VERSION 5.7 ;
  NOWIREEXTENSIONATPIN ON ;
  DIVIDERCHAR "/" ;
  BUSBITCHARS "[]" ;
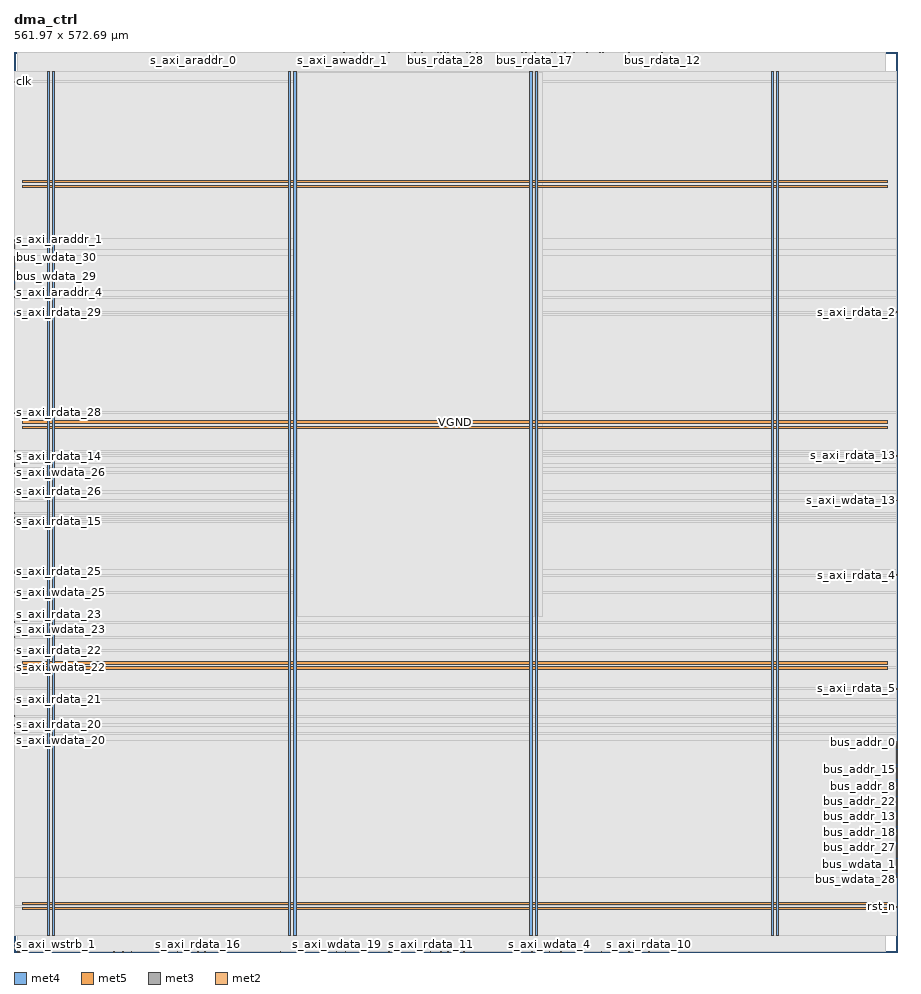
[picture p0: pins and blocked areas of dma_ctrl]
MACRO dma_ctrl
  CLASS BLOCK ;
  FOREIGN dma_ctrl ;
  ORIGIN 0.000 0.000 ;
  SIZE 561.970 BY 572.690 ;
  PIN VGND
    DIRECTION INOUT ;
    USE GROUND ;
    PORT
      LAYER met4 ;
        RECT 24.340 10.640 25.940 560.560 ;
    END
    PORT
      LAYER met4 ;
        RECT 177.940 10.640 179.540 560.560 ;
    END
    PORT
      LAYER met4 ;
        RECT 331.540 10.640 333.140 560.560 ;
    END
    PORT
      LAYER met4 ;
        RECT 485.140 10.640 486.740 560.560 ;
    END
    PORT
      LAYER met5 ;
        RECT 5.520 30.030 556.140 31.630 ;
    END
    PORT
      LAYER met5 ;
        RECT 5.520 183.210 556.140 184.810 ;
    END
    PORT
      LAYER met5 ;
        RECT 5.520 336.390 556.140 337.990 ;
    END
    PORT
      LAYER met5 ;
        RECT 5.520 489.570 556.140 491.170 ;
    END
  END VGND
  PIN VPWR
    DIRECTION INOUT ;
    USE POWER ;
    PORT
      LAYER met4 ;
        RECT 21.040 10.640 22.640 560.560 ;
    END
    PORT
      LAYER met4 ;
        RECT 174.640 10.640 176.240 560.560 ;
    END
    PORT
      LAYER met4 ;
        RECT 328.240 10.640 329.840 560.560 ;
    END
    PORT
      LAYER met4 ;
        RECT 481.840 10.640 483.440 560.560 ;
    END
    PORT
      LAYER met5 ;
        RECT 5.520 26.730 556.140 28.330 ;
    END
    PORT
      LAYER met5 ;
        RECT 5.520 179.910 556.140 181.510 ;
    END
    PORT
      LAYER met5 ;
        RECT 5.520 333.090 556.140 334.690 ;
    END
    PORT
      LAYER met5 ;
        RECT 5.520 486.270 556.140 487.870 ;
    END
  END VPWR
  PIN bus_addr_0
    DIRECTION OUTPUT ;
    USE SIGNAL ;
    ANTENNAGATEAREA 0.434700 ;
    ANTENNADIFFAREA 0.775300 ;
    PORT
      LAYER met3 ;
        RECT 561.370 133.320 561.970 133.920 ;
    END
  END bus_addr_0
  PIN bus_addr_1
    DIRECTION OUTPUT ;
    USE SIGNAL ;
    ANTENNAGATEAREA 0.434700 ;
    ANTENNADIFFAREA 0.775300 ;
    PORT
      LAYER met3 ;
        RECT 561.370 96.600 561.970 97.200 ;
    END
  END bus_addr_1
  PIN bus_addr_10
    DIRECTION OUTPUT ;
    USE SIGNAL ;
    ANTENNAGATEAREA 0.434700 ;
    ANTENNADIFFAREA 0.775300 ;
    PORT
      LAYER met3 ;
        RECT 561.370 123.800 561.970 124.400 ;
    END
  END bus_addr_10
  PIN bus_addr_11
    DIRECTION OUTPUT ;
    USE SIGNAL ;
    ANTENNAGATEAREA 0.434700 ;
    ANTENNADIFFAREA 0.775300 ;
    PORT
      LAYER met3 ;
        RECT 561.370 91.160 561.970 91.760 ;
    END
  END bus_addr_11
  PIN bus_addr_12
    DIRECTION OUTPUT ;
    USE SIGNAL ;
    ANTENNAGATEAREA 0.434700 ;
    ANTENNADIFFAREA 0.775300 ;
    PORT
      LAYER met3 ;
        RECT 561.370 129.240 561.970 129.840 ;
    END
  END bus_addr_12
  PIN bus_addr_13
    DIRECTION OUTPUT ;
    USE SIGNAL ;
    ANTENNAGATEAREA 0.434700 ;
    ANTENNADIFFAREA 0.775300 ;
    PORT
      LAYER met3 ;
        RECT 561.370 85.720 561.970 86.320 ;
    END
  END bus_addr_13
  PIN bus_addr_14
    DIRECTION OUTPUT ;
    USE SIGNAL ;
    ANTENNAGATEAREA 0.434700 ;
    ANTENNADIFFAREA 0.775300 ;
    PORT
      LAYER met3 ;
        RECT 561.370 84.360 561.970 84.960 ;
    END
  END bus_addr_14
  PIN bus_addr_15
    DIRECTION OUTPUT ;
    USE SIGNAL ;
    ANTENNAGATEAREA 0.434700 ;
    ANTENNADIFFAREA 0.775300 ;
    PORT
      LAYER met3 ;
        RECT 561.370 115.640 561.970 116.240 ;
    END
  END bus_addr_15
  PIN bus_addr_16
    DIRECTION OUTPUT ;
    USE SIGNAL ;
    ANTENNAGATEAREA 0.434700 ;
    ANTENNADIFFAREA 0.775300 ;
    PORT
      LAYER met3 ;
        RECT 561.370 83.000 561.970 83.600 ;
    END
  END bus_addr_16
  PIN bus_addr_17
    DIRECTION OUTPUT ;
    USE SIGNAL ;
    ANTENNAGATEAREA 0.434700 ;
    ANTENNADIFFAREA 0.775300 ;
    PORT
      LAYER met3 ;
        RECT 561.370 114.280 561.970 114.880 ;
    END
  END bus_addr_17
  PIN bus_addr_18
    DIRECTION OUTPUT ;
    USE SIGNAL ;
    ANTENNAGATEAREA 0.434700 ;
    ANTENNADIFFAREA 0.775300 ;
    PORT
      LAYER met3 ;
        RECT 561.370 80.280 561.970 80.880 ;
    END
  END bus_addr_18
  PIN bus_addr_19
    DIRECTION OUTPUT ;
    USE SIGNAL ;
    ANTENNAGATEAREA 0.434700 ;
    ANTENNADIFFAREA 0.775300 ;
    PORT
      LAYER met3 ;
        RECT 561.370 93.880 561.970 94.480 ;
    END
  END bus_addr_19
  PIN bus_addr_2
    DIRECTION OUTPUT ;
    USE SIGNAL ;
    ANTENNAGATEAREA 0.434700 ;
    ANTENNADIFFAREA 0.775300 ;
    PORT
      LAYER met3 ;
        RECT 561.370 78.920 561.970 79.520 ;
    END
  END bus_addr_2
  PIN bus_addr_20
    DIRECTION OUTPUT ;
    USE SIGNAL ;
    ANTENNAGATEAREA 0.434700 ;
    ANTENNADIFFAREA 0.775300 ;
    PORT
      LAYER met3 ;
        RECT 561.370 77.560 561.970 78.160 ;
    END
  END bus_addr_20
  PIN bus_addr_21
    DIRECTION OUTPUT ;
    USE SIGNAL ;
    ANTENNAGATEAREA 0.434700 ;
    ANTENNADIFFAREA 0.775300 ;
    PORT
      LAYER met3 ;
        RECT 561.370 125.160 561.970 125.760 ;
    END
  END bus_addr_21
  PIN bus_addr_22
    DIRECTION OUTPUT ;
    USE SIGNAL ;
    ANTENNAGATEAREA 0.434700 ;
    ANTENNADIFFAREA 0.775300 ;
    PORT
      LAYER met3 ;
        RECT 561.370 95.240 561.970 95.840 ;
    END
  END bus_addr_22
  PIN bus_addr_23
    DIRECTION OUTPUT ;
    USE SIGNAL ;
    ANTENNAGATEAREA 0.434700 ;
    ANTENNADIFFAREA 0.775300 ;
    PORT
      LAYER met3 ;
        RECT 561.370 74.840 561.970 75.440 ;
    END
  END bus_addr_23
  PIN bus_addr_24
    DIRECTION OUTPUT ;
    USE SIGNAL ;
    ANTENNAGATEAREA 0.434700 ;
    ANTENNADIFFAREA 0.775300 ;
    PORT
      LAYER met3 ;
        RECT 561.370 73.480 561.970 74.080 ;
    END
  END bus_addr_24
  PIN bus_addr_25
    DIRECTION OUTPUT ;
    USE SIGNAL ;
    ANTENNAGATEAREA 0.434700 ;
    ANTENNADIFFAREA 0.775300 ;
    PORT
      LAYER met3 ;
        RECT 561.370 72.120 561.970 72.720 ;
    END
  END bus_addr_25
  PIN bus_addr_26
    DIRECTION OUTPUT ;
    USE SIGNAL ;
    ANTENNAGATEAREA 0.434700 ;
    ANTENNADIFFAREA 0.775300 ;
    PORT
      LAYER met3 ;
        RECT 561.370 117.000 561.970 117.600 ;
    END
  END bus_addr_26
  PIN bus_addr_27
    DIRECTION OUTPUT ;
    USE SIGNAL ;
    ANTENNAGATEAREA 0.434700 ;
    ANTENNADIFFAREA 0.775300 ;
    PORT
      LAYER met3 ;
        RECT 561.370 70.760 561.970 71.360 ;
    END
  END bus_addr_27
  PIN bus_addr_28
    DIRECTION OUTPUT ;
    USE SIGNAL ;
    ANTENNAGATEAREA 0.434700 ;
    ANTENNADIFFAREA 0.775300 ;
    PORT
      LAYER met3 ;
        RECT 561.370 69.400 561.970 70.000 ;
    END
  END bus_addr_28
  PIN bus_addr_29
    DIRECTION OUTPUT ;
    USE SIGNAL ;
    ANTENNAGATEAREA 0.434700 ;
    ANTENNADIFFAREA 0.775300 ;
    PORT
      LAYER met3 ;
        RECT 561.370 68.040 561.970 68.640 ;
    END
  END bus_addr_29
  PIN bus_addr_3
    DIRECTION OUTPUT ;
    USE SIGNAL ;
    ANTENNAGATEAREA 0.434700 ;
    ANTENNADIFFAREA 0.775300 ;
    PORT
      LAYER met3 ;
        RECT 561.370 97.960 561.970 98.560 ;
    END
  END bus_addr_3
  PIN bus_addr_30
    DIRECTION OUTPUT ;
    USE SIGNAL ;
    ANTENNAGATEAREA 0.434700 ;
    ANTENNADIFFAREA 0.775300 ;
    PORT
      LAYER met3 ;
        RECT 561.370 66.680 561.970 67.280 ;
    END
  END bus_addr_30
  PIN bus_addr_31
    DIRECTION OUTPUT ;
    USE SIGNAL ;
    ANTENNAGATEAREA 0.434700 ;
    ANTENNADIFFAREA 0.775300 ;
    PORT
      LAYER met3 ;
        RECT 561.370 118.360 561.970 118.960 ;
    END
  END bus_addr_31
  PIN bus_addr_4
    DIRECTION OUTPUT ;
    USE SIGNAL ;
    ANTENNAGATEAREA 0.434700 ;
    ANTENNADIFFAREA 0.775300 ;
    PORT
      LAYER met3 ;
        RECT 561.370 63.960 561.970 64.560 ;
    END
  END bus_addr_4
  PIN bus_addr_5
    DIRECTION OUTPUT ;
    USE SIGNAL ;
    ANTENNAGATEAREA 0.434700 ;
    ANTENNADIFFAREA 0.775300 ;
    PORT
      LAYER met3 ;
        RECT 561.370 99.320 561.970 99.920 ;
    END
  END bus_addr_5
  PIN bus_addr_6
    DIRECTION OUTPUT ;
    USE SIGNAL ;
    ANTENNAGATEAREA 0.434700 ;
    ANTENNADIFFAREA 0.775300 ;
    PORT
      LAYER met3 ;
        RECT 561.370 62.600 561.970 63.200 ;
    END
  END bus_addr_6
  PIN bus_addr_7
    DIRECTION OUTPUT ;
    USE SIGNAL ;
    ANTENNAGATEAREA 0.434700 ;
    ANTENNADIFFAREA 0.775300 ;
    PORT
      LAYER met3 ;
        RECT 561.370 88.440 561.970 89.040 ;
    END
  END bus_addr_7
  PIN bus_addr_8
    DIRECTION OUTPUT ;
    USE SIGNAL ;
    ANTENNAGATEAREA 0.434700 ;
    ANTENNADIFFAREA 0.775300 ;
    PORT
      LAYER met3 ;
        RECT 561.370 104.760 561.970 105.360 ;
    END
  END bus_addr_8
  PIN bus_addr_9
    DIRECTION OUTPUT ;
    USE SIGNAL ;
    ANTENNAGATEAREA 0.434700 ;
    ANTENNADIFFAREA 0.775300 ;
    PORT
      LAYER met3 ;
        RECT 561.370 100.680 561.970 101.280 ;
    END
  END bus_addr_9
  PIN bus_rd
    DIRECTION OUTPUT ;
    USE SIGNAL ;
    ANTENNAGATEAREA 0.434700 ;
    ANTENNADIFFAREA 0.775300 ;
    PORT
      LAYER met3 ;
        RECT 0.000 423.000 0.600 423.600 ;
    END
  END bus_rd
  PIN bus_rdata_0
    DIRECTION INPUT ;
    USE SIGNAL ;
    ANTENNAGATEAREA 0.647700 ;
    ANTENNADIFFAREA 0.434700 ;
    PORT
      LAYER met2 ;
        RECT 310.130 572.410 310.410 572.690 ;
    END
  END bus_rdata_0
  PIN bus_rdata_1
    DIRECTION INPUT ;
    USE SIGNAL ;
    ANTENNAGATEAREA 0.647700 ;
    ANTENNADIFFAREA 0.434700 ;
    PORT
      LAYER met2 ;
        RECT 252.170 572.410 252.450 572.690 ;
    END
  END bus_rdata_1
  PIN bus_rdata_10
    DIRECTION INPUT ;
    USE SIGNAL ;
    ANTENNAGATEAREA 0.647700 ;
    ANTENNADIFFAREA 0.434700 ;
    PORT
      LAYER met2 ;
        RECT 342.330 572.410 342.610 572.690 ;
    END
  END bus_rdata_10
  PIN bus_rdata_11
    DIRECTION INPUT ;
    USE SIGNAL ;
    ANTENNAGATEAREA 0.647700 ;
    ANTENNADIFFAREA 0.434700 ;
    PORT
      LAYER met2 ;
        RECT 358.890 572.410 359.170 572.690 ;
    END
  END bus_rdata_11
  PIN bus_rdata_12
    DIRECTION INPUT ;
    USE SIGNAL ;
    ANTENNAGATEAREA 0.647700 ;
    ANTENNADIFFAREA 0.434700 ;
    PORT
      LAYER met2 ;
        RECT 412.250 572.410 412.530 572.690 ;
    END
  END bus_rdata_12
  PIN bus_rdata_13
    DIRECTION INPUT ;
    USE SIGNAL ;
    ANTENNAGATEAREA 0.647700 ;
    ANTENNADIFFAREA 0.434700 ;
    PORT
      LAYER met2 ;
        RECT 372.690 572.410 372.970 572.690 ;
    END
  END bus_rdata_13
  PIN bus_rdata_14
    DIRECTION INPUT ;
    USE SIGNAL ;
    ANTENNAGATEAREA 0.647700 ;
    ANTENNADIFFAREA 0.434700 ;
    PORT
      LAYER met2 ;
        RECT 392.010 572.410 392.290 572.690 ;
    END
  END bus_rdata_14
  PIN bus_rdata_15
    DIRECTION INPUT ;
    USE SIGNAL ;
    ANTENNAGATEAREA 0.647700 ;
    ANTENNADIFFAREA 0.434700 ;
    PORT
      LAYER met2 ;
        RECT 259.530 572.410 259.810 572.690 ;
    END
  END bus_rdata_15
  PIN bus_rdata_16
    DIRECTION INPUT ;
    USE SIGNAL ;
    ANTENNAGATEAREA 0.647700 ;
    ANTENNADIFFAREA 0.434700 ;
    PORT
      LAYER met2 ;
        RECT 364.410 572.410 364.690 572.690 ;
    END
  END bus_rdata_16
  PIN bus_rdata_17
    DIRECTION INPUT ;
    USE SIGNAL ;
    ANTENNAGATEAREA 0.647700 ;
    ANTENNADIFFAREA 0.434700 ;
    PORT
      LAYER met2 ;
        RECT 331.290 572.410 331.570 572.690 ;
    END
  END bus_rdata_17
  PIN bus_rdata_18
    DIRECTION INPUT ;
    USE SIGNAL ;
    ANTENNAGATEAREA 0.647700 ;
    ANTENNADIFFAREA 0.434700 ;
    PORT
      LAYER met2 ;
        RECT 325.770 572.410 326.050 572.690 ;
    END
  END bus_rdata_18
  PIN bus_rdata_19
    DIRECTION INPUT ;
    USE SIGNAL ;
    ANTENNAGATEAREA 0.647700 ;
    ANTENNADIFFAREA 0.434700 ;
    PORT
      LAYER met2 ;
        RECT 356.130 572.410 356.410 572.690 ;
    END
  END bus_rdata_19
  PIN bus_rdata_2
    DIRECTION INPUT ;
    USE SIGNAL ;
    ANTENNAGATEAREA 0.647700 ;
    ANTENNADIFFAREA 0.434700 ;
    PORT
      LAYER met2 ;
        RECT 303.690 572.410 303.970 572.690 ;
    END
  END bus_rdata_2
  PIN bus_rdata_20
    DIRECTION INPUT ;
    USE SIGNAL ;
    ANTENNAGATEAREA 0.647700 ;
    ANTENNADIFFAREA 0.434700 ;
    PORT
      LAYER met2 ;
        RECT 350.610 572.410 350.890 572.690 ;
    END
  END bus_rdata_20
  PIN bus_rdata_21
    DIRECTION INPUT ;
    USE SIGNAL ;
    ANTENNAGATEAREA 0.647700 ;
    ANTENNADIFFAREA 0.434700 ;
    PORT
      LAYER met2 ;
        RECT 391.090 572.410 391.370 572.690 ;
    END
  END bus_rdata_21
  PIN bus_rdata_22
    DIRECTION INPUT ;
    USE SIGNAL ;
    ANTENNAGATEAREA 0.647700 ;
    ANTENNADIFFAREA 0.434700 ;
    PORT
      LAYER met2 ;
        RECT 411.330 572.410 411.610 572.690 ;
    END
  END bus_rdata_22
  PIN bus_rdata_23
    DIRECTION INPUT ;
    USE SIGNAL ;
    ANTENNAGATEAREA 0.647700 ;
    ANTENNADIFFAREA 0.434700 ;
    PORT
      LAYER met2 ;
        RECT 288.970 572.410 289.250 572.690 ;
    END
  END bus_rdata_23
  PIN bus_rdata_24
    DIRECTION INPUT ;
    USE SIGNAL ;
    ANTENNAGATEAREA 0.647700 ;
    ANTENNADIFFAREA 0.434700 ;
    PORT
      LAYER met2 ;
        RECT 307.370 572.410 307.650 572.690 ;
    END
  END bus_rdata_24
  PIN bus_rdata_25
    DIRECTION INPUT ;
    USE SIGNAL ;
    ANTENNAGATEAREA 0.647700 ;
    ANTENNADIFFAREA 0.434700 ;
    PORT
      LAYER met2 ;
        RECT 324.850 572.410 325.130 572.690 ;
    END
  END bus_rdata_25
  PIN bus_rdata_26
    DIRECTION INPUT ;
    USE SIGNAL ;
    ANTENNAGATEAREA 0.647700 ;
    ANTENNADIFFAREA 0.434700 ;
    PORT
      LAYER met2 ;
        RECT 390.170 572.410 390.450 572.690 ;
    END
  END bus_rdata_26
  PIN bus_rdata_27
    DIRECTION INPUT ;
    USE SIGNAL ;
    ANTENNAGATEAREA 0.647700 ;
    ANTENNADIFFAREA 0.434700 ;
    PORT
      LAYER met2 ;
        RECT 409.490 572.410 409.770 572.690 ;
    END
  END bus_rdata_27
  PIN bus_rdata_28
    DIRECTION INPUT ;
    USE SIGNAL ;
    ANTENNAGATEAREA 0.647700 ;
    ANTENNADIFFAREA 0.434700 ;
    PORT
      LAYER met2 ;
        RECT 274.250 572.410 274.530 572.690 ;
    END
  END bus_rdata_28
  PIN bus_rdata_29
    DIRECTION INPUT ;
    USE SIGNAL ;
    ANTENNAGATEAREA 0.647700 ;
    ANTENNADIFFAREA 0.434700 ;
    PORT
      LAYER met2 ;
        RECT 373.610 572.410 373.890 572.690 ;
    END
  END bus_rdata_29
  PIN bus_rdata_3
    DIRECTION INPUT ;
    USE SIGNAL ;
    ANTENNAGATEAREA 0.647700 ;
    ANTENNADIFFAREA 0.434700 ;
    PORT
      LAYER met2 ;
        RECT 271.490 572.410 271.770 572.690 ;
    END
  END bus_rdata_3
  PIN bus_rdata_30
    DIRECTION INPUT ;
    USE SIGNAL ;
    ANTENNAGATEAREA 0.647700 ;
    ANTENNADIFFAREA 0.434700 ;
    PORT
      LAYER met2 ;
        RECT 344.170 572.410 344.450 572.690 ;
    END
  END bus_rdata_30
  PIN bus_rdata_31
    DIRECTION INPUT ;
    USE SIGNAL ;
    ANTENNAGATEAREA 0.647700 ;
    ANTENNADIFFAREA 0.434700 ;
    PORT
      LAYER met2 ;
        RECT 323.010 572.410 323.290 572.690 ;
    END
  END bus_rdata_31
  PIN bus_rdata_4
    DIRECTION INPUT ;
    USE SIGNAL ;
    ANTENNAGATEAREA 0.647700 ;
    ANTENNADIFFAREA 0.434700 ;
    PORT
      LAYER met2 ;
        RECT 266.890 572.410 267.170 572.690 ;
    END
  END bus_rdata_4
  PIN bus_rdata_5
    DIRECTION INPUT ;
    USE SIGNAL ;
    ANTENNAGATEAREA 0.647700 ;
    ANTENNADIFFAREA 0.434700 ;
    PORT
      LAYER met2 ;
        RECT 276.090 572.410 276.370 572.690 ;
    END
  END bus_rdata_5
  PIN bus_rdata_6
    DIRECTION INPUT ;
    USE SIGNAL ;
    ANTENNAGATEAREA 0.647700 ;
    ANTENNADIFFAREA 0.434700 ;
    PORT
      LAYER met2 ;
        RECT 295.410 572.410 295.690 572.690 ;
    END
  END bus_rdata_6
  PIN bus_rdata_7
    DIRECTION INPUT ;
    USE SIGNAL ;
    ANTENNAGATEAREA 0.647700 ;
    ANTENNADIFFAREA 0.434700 ;
    PORT
      LAYER met2 ;
        RECT 415.010 572.410 415.290 572.690 ;
    END
  END bus_rdata_7
  PIN bus_rdata_8
    DIRECTION INPUT ;
    USE SIGNAL ;
    ANTENNAGATEAREA 0.647700 ;
    ANTENNADIFFAREA 0.434700 ;
    PORT
      LAYER met2 ;
        RECT 408.570 572.410 408.850 572.690 ;
    END
  END bus_rdata_8
  PIN bus_rdata_9
    DIRECTION INPUT ;
    USE SIGNAL ;
    ANTENNAGATEAREA 0.647700 ;
    ANTENNADIFFAREA 0.434700 ;
    PORT
      LAYER met2 ;
        RECT 375.450 572.410 375.730 572.690 ;
    END
  END bus_rdata_9
  PIN bus_ready
    DIRECTION INPUT ;
    USE SIGNAL ;
    ANTENNAGATEAREA 0.647700 ;
    ANTENNADIFFAREA 0.434700 ;
    PORT
      LAYER met2 ;
        RECT 374.530 572.410 374.810 572.690 ;
    END
  END bus_ready
  PIN bus_wdata_0
    DIRECTION OUTPUT ;
    USE SIGNAL ;
    ANTENNAGATEAREA 0.434700 ;
    ANTENNADIFFAREA 0.775300 ;
    PORT
      LAYER met3 ;
        RECT 561.370 126.520 561.970 127.120 ;
    END
  END bus_wdata_0
  PIN bus_wdata_1
    DIRECTION OUTPUT ;
    USE SIGNAL ;
    ANTENNAGATEAREA 0.434700 ;
    ANTENNADIFFAREA 0.775300 ;
    PORT
      LAYER met3 ;
        RECT 561.370 59.880 561.970 60.480 ;
    END
  END bus_wdata_1
  PIN bus_wdata_10
    DIRECTION OUTPUT ;
    USE SIGNAL ;
    ANTENNAGATEAREA 0.434700 ;
    ANTENNADIFFAREA 0.775300 ;
    PORT
      LAYER met3 ;
        RECT 561.370 119.720 561.970 120.320 ;
    END
  END bus_wdata_10
  PIN bus_wdata_11
    DIRECTION OUTPUT ;
    USE SIGNAL ;
    ANTENNAGATEAREA 0.434700 ;
    ANTENNADIFFAREA 0.775300 ;
    PORT
      LAYER met3 ;
        RECT 561.370 102.040 561.970 102.640 ;
    END
  END bus_wdata_11
  PIN bus_wdata_12
    DIRECTION OUTPUT ;
    USE SIGNAL ;
    ANTENNAGATEAREA 0.434700 ;
    ANTENNADIFFAREA 0.775300 ;
    PORT
      LAYER met3 ;
        RECT 561.370 76.200 561.970 76.800 ;
    END
  END bus_wdata_12
  PIN bus_wdata_13
    DIRECTION OUTPUT ;
    USE SIGNAL ;
    ANTENNAGATEAREA 0.434700 ;
    ANTENNADIFFAREA 0.775300 ;
    PORT
      LAYER met3 ;
        RECT 561.370 131.960 561.970 132.560 ;
    END
  END bus_wdata_13
  PIN bus_wdata_14
    DIRECTION OUTPUT ;
    USE SIGNAL ;
    ANTENNAGATEAREA 0.434700 ;
    ANTENNADIFFAREA 0.775300 ;
    PORT
      LAYER met3 ;
        RECT 561.370 57.160 561.970 57.760 ;
    END
  END bus_wdata_14
  PIN bus_wdata_15
    DIRECTION OUTPUT ;
    USE SIGNAL ;
    ANTENNAGATEAREA 0.434700 ;
    ANTENNADIFFAREA 0.775300 ;
    PORT
      LAYER met3 ;
        RECT 561.370 103.400 561.970 104.000 ;
    END
  END bus_wdata_15
  PIN bus_wdata_16
    DIRECTION OUTPUT ;
    USE SIGNAL ;
    ANTENNAGATEAREA 0.434700 ;
    ANTENNADIFFAREA 0.775300 ;
    PORT
      LAYER met3 ;
        RECT 561.370 81.640 561.970 82.240 ;
    END
  END bus_wdata_16
  PIN bus_wdata_17
    DIRECTION OUTPUT ;
    USE SIGNAL ;
    ANTENNAGATEAREA 0.434700 ;
    ANTENNADIFFAREA 0.775300 ;
    PORT
      LAYER met3 ;
        RECT 561.370 55.800 561.970 56.400 ;
    END
  END bus_wdata_17
  PIN bus_wdata_18
    DIRECTION OUTPUT ;
    USE SIGNAL ;
    ANTENNAGATEAREA 0.434700 ;
    ANTENNADIFFAREA 0.775300 ;
    PORT
      LAYER met3 ;
        RECT 561.370 127.880 561.970 128.480 ;
    END
  END bus_wdata_18
  PIN bus_wdata_19
    DIRECTION OUTPUT ;
    USE SIGNAL ;
    ANTENNAGATEAREA 0.434700 ;
    ANTENNADIFFAREA 0.775300 ;
    PORT
      LAYER met3 ;
        RECT 561.370 121.080 561.970 121.680 ;
    END
  END bus_wdata_19
  PIN bus_wdata_2
    DIRECTION OUTPUT ;
    USE SIGNAL ;
    ANTENNAGATEAREA 0.434700 ;
    ANTENNADIFFAREA 0.775300 ;
    PORT
      LAYER met3 ;
        RECT 561.370 130.600 561.970 131.200 ;
    END
  END bus_wdata_2
  PIN bus_wdata_20
    DIRECTION OUTPUT ;
    USE SIGNAL ;
    ANTENNAGATEAREA 0.434700 ;
    ANTENNADIFFAREA 0.775300 ;
    PORT
      LAYER met3 ;
        RECT 561.370 108.840 561.970 109.440 ;
    END
  END bus_wdata_20
  PIN bus_wdata_21
    DIRECTION OUTPUT ;
    USE SIGNAL ;
    ANTENNAGATEAREA 0.434700 ;
    ANTENNADIFFAREA 0.775300 ;
    PORT
      LAYER met3 ;
        RECT 561.370 92.520 561.970 93.120 ;
    END
  END bus_wdata_21
  PIN bus_wdata_22
    DIRECTION OUTPUT ;
    USE SIGNAL ;
    ANTENNAGATEAREA 0.434700 ;
    ANTENNADIFFAREA 0.775300 ;
    PORT
      LAYER met3 ;
        RECT 561.370 106.120 561.970 106.720 ;
    END
  END bus_wdata_22
  PIN bus_wdata_23
    DIRECTION OUTPUT ;
    USE SIGNAL ;
    ANTENNAGATEAREA 0.434700 ;
    ANTENNADIFFAREA 0.775300 ;
    PORT
      LAYER met3 ;
        RECT 561.370 61.240 561.970 61.840 ;
    END
  END bus_wdata_23
  PIN bus_wdata_24
    DIRECTION OUTPUT ;
    USE SIGNAL ;
    ANTENNAGATEAREA 0.434700 ;
    ANTENNADIFFAREA 0.775300 ;
    PORT
      LAYER met3 ;
        RECT 561.370 58.520 561.970 59.120 ;
    END
  END bus_wdata_24
  PIN bus_wdata_25
    DIRECTION OUTPUT ;
    USE SIGNAL ;
    ANTENNAGATEAREA 0.434700 ;
    ANTENNADIFFAREA 0.775300 ;
    PORT
      LAYER met3 ;
        RECT 561.370 51.720 561.970 52.320 ;
    END
  END bus_wdata_25
  PIN bus_wdata_26
    DIRECTION OUTPUT ;
    USE SIGNAL ;
    ANTENNAGATEAREA 0.434700 ;
    ANTENNADIFFAREA 0.775300 ;
    PORT
      LAYER met3 ;
        RECT 561.370 107.480 561.970 108.080 ;
    END
  END bus_wdata_26
  PIN bus_wdata_27
    DIRECTION OUTPUT ;
    USE SIGNAL ;
    ANTENNAGATEAREA 0.434700 ;
    ANTENNADIFFAREA 0.775300 ;
    PORT
      LAYER met3 ;
        RECT 561.370 54.440 561.970 55.040 ;
    END
  END bus_wdata_27
  PIN bus_wdata_28
    DIRECTION OUTPUT ;
    USE SIGNAL ;
    ANTENNAGATEAREA 0.434700 ;
    ANTENNADIFFAREA 0.775300 ;
    PORT
      LAYER met3 ;
        RECT 561.370 50.360 561.970 50.960 ;
    END
  END bus_wdata_28
  PIN bus_wdata_29
    DIRECTION OUTPUT ;
    USE SIGNAL ;
    ANTENNAGATEAREA 0.434700 ;
    ANTENNADIFFAREA 0.775300 ;
    PORT
      LAYER met3 ;
        RECT 0.000 429.800 0.600 430.400 ;
    END
  END bus_wdata_29
  PIN bus_wdata_3
    DIRECTION OUTPUT ;
    USE SIGNAL ;
    ANTENNAGATEAREA 0.434700 ;
    ANTENNADIFFAREA 0.775300 ;
    PORT
      LAYER met3 ;
        RECT 561.370 112.920 561.970 113.520 ;
    END
  END bus_wdata_3
  PIN bus_wdata_30
    DIRECTION OUTPUT ;
    USE SIGNAL ;
    ANTENNAGATEAREA 0.434700 ;
    ANTENNADIFFAREA 0.775300 ;
    PORT
      LAYER met3 ;
        RECT 0.000 436.600 0.600 437.200 ;
    END
  END bus_wdata_30
  PIN bus_wdata_31
    DIRECTION OUTPUT ;
    USE SIGNAL ;
    ANTENNAGATEAREA 0.434700 ;
    ANTENNADIFFAREA 0.775300 ;
    PORT
      LAYER met3 ;
        RECT 0.000 432.520 0.600 433.120 ;
    END
  END bus_wdata_31
  PIN bus_wdata_4
    DIRECTION OUTPUT ;
    USE SIGNAL ;
    ANTENNAGATEAREA 0.434700 ;
    ANTENNADIFFAREA 0.775300 ;
    PORT
      LAYER met3 ;
        RECT 561.370 122.440 561.970 123.040 ;
    END
  END bus_wdata_4
  PIN bus_wdata_5
    DIRECTION OUTPUT ;
    USE SIGNAL ;
    ANTENNAGATEAREA 0.434700 ;
    ANTENNADIFFAREA 0.775300 ;
    PORT
      LAYER met3 ;
        RECT 561.370 53.080 561.970 53.680 ;
    END
  END bus_wdata_5
  PIN bus_wdata_6
    DIRECTION OUTPUT ;
    USE SIGNAL ;
    ANTENNAGATEAREA 0.434700 ;
    ANTENNADIFFAREA 0.775300 ;
    PORT
      LAYER met3 ;
        RECT 561.370 89.800 561.970 90.400 ;
    END
  END bus_wdata_6
  PIN bus_wdata_7
    DIRECTION OUTPUT ;
    USE SIGNAL ;
    ANTENNAGATEAREA 0.434700 ;
    ANTENNADIFFAREA 0.775300 ;
    PORT
      LAYER met3 ;
        RECT 561.370 49.000 561.970 49.600 ;
    END
  END bus_wdata_7
  PIN bus_wdata_8
    DIRECTION OUTPUT ;
    USE SIGNAL ;
    ANTENNAGATEAREA 0.434700 ;
    ANTENNADIFFAREA 0.775300 ;
    PORT
      LAYER met3 ;
        RECT 561.370 110.200 561.970 110.800 ;
    END
  END bus_wdata_8
  PIN bus_wdata_9
    DIRECTION OUTPUT ;
    USE SIGNAL ;
    ANTENNAGATEAREA 0.434700 ;
    ANTENNADIFFAREA 0.775300 ;
    PORT
      LAYER met3 ;
        RECT 561.370 47.640 561.970 48.240 ;
    END
  END bus_wdata_9
  PIN bus_wr
    DIRECTION OUTPUT ;
    USE SIGNAL ;
    ANTENNAGATEAREA 0.434700 ;
    ANTENNADIFFAREA 0.775300 ;
    PORT
      LAYER met3 ;
        RECT 0.000 431.160 0.600 431.760 ;
    END
  END bus_wr
  PIN clk
    DIRECTION INPUT ;
    USE SIGNAL ;
    ANTENNAGATEAREA 1.286700 ;
    ANTENNADIFFAREA 0.434700 ;
    PORT
      LAYER met3 ;
        RECT 0.000 553.560 0.600 554.160 ;
    END
  END clk
  PIN irq
    DIRECTION OUTPUT ;
    USE SIGNAL ;
    ANTENNAGATEAREA 0.434700 ;
    ANTENNADIFFAREA 0.775300 ;
    PORT
      LAYER met3 ;
        RECT 0.000 433.880 0.600 434.480 ;
    END
  END irq
  PIN rst_n
    DIRECTION INPUT ;
    USE SIGNAL ;
    ANTENNAGATEAREA 0.631200 ;
    ANTENNADIFFAREA 0.434700 ;
    PORT
      LAYER met3 ;
        RECT 561.370 28.600 561.970 29.200 ;
    END
  END rst_n
  PIN s_axi_araddr_0
    DIRECTION INPUT ;
    USE SIGNAL ;
    ANTENNAGATEAREA 0.647700 ;
    ANTENNADIFFAREA 0.434700 ;
    PORT
      LAYER met2 ;
        RECT 114.170 572.410 114.450 572.690 ;
    END
  END s_axi_araddr_0
  PIN s_axi_araddr_1
    DIRECTION INPUT ;
    USE SIGNAL ;
    ANTENNAGATEAREA 0.647700 ;
    ANTENNADIFFAREA 0.434700 ;
    PORT
      LAYER met3 ;
        RECT 0.000 452.920 0.600 453.520 ;
    END
  END s_axi_araddr_1
  PIN s_axi_araddr_10
    DIRECTION INPUT ;
    USE SIGNAL ;
    ANTENNAGATEAREA 0.647700 ;
    ANTENNADIFFAREA 0.434700 ;
    PORT
      LAYER met3 ;
        RECT 0.000 451.560 0.600 452.160 ;
    END
  END s_axi_araddr_10
  PIN s_axi_araddr_11
    DIRECTION INPUT ;
    USE SIGNAL ;
    ANTENNAGATEAREA 0.647700 ;
    ANTENNADIFFAREA 0.434700 ;
    PORT
      LAYER met2 ;
        RECT 136.250 572.410 136.530 572.690 ;
    END
  END s_axi_araddr_11
  PIN s_axi_araddr_2
    DIRECTION INPUT ;
    USE SIGNAL ;
    ANTENNAGATEAREA 0.647700 ;
    ANTENNADIFFAREA 0.434700 ;
    PORT
      LAYER met3 ;
        RECT 0.000 437.960 0.600 438.560 ;
    END
  END s_axi_araddr_2
  PIN s_axi_araddr_3
    DIRECTION INPUT ;
    USE SIGNAL ;
    ANTENNAGATEAREA 0.647700 ;
    ANTENNADIFFAREA 0.434700 ;
    PORT
      LAYER met3 ;
        RECT 0.000 440.680 0.600 441.280 ;
    END
  END s_axi_araddr_3
  PIN s_axi_araddr_4
    DIRECTION INPUT ;
    USE SIGNAL ;
    ANTENNAGATEAREA 0.647700 ;
    ANTENNADIFFAREA 0.434700 ;
    PORT
      LAYER met3 ;
        RECT 0.000 424.360 0.600 424.960 ;
    END
  END s_axi_araddr_4
  PIN s_axi_araddr_5
    DIRECTION INPUT ;
    USE SIGNAL ;
    ANTENNAGATEAREA 0.647700 ;
    ANTENNADIFFAREA 0.434700 ;
    PORT
      LAYER met3 ;
        RECT 0.000 447.480 0.600 448.080 ;
    END
  END s_axi_araddr_5
  PIN s_axi_araddr_6
    DIRECTION INPUT ;
    USE SIGNAL ;
    ANTENNAGATEAREA 0.647700 ;
    ANTENNADIFFAREA 0.434700 ;
    PORT
      LAYER met3 ;
        RECT 0.000 427.080 0.600 427.680 ;
    END
  END s_axi_araddr_6
  PIN s_axi_araddr_7
    DIRECTION INPUT ;
    USE SIGNAL ;
    ANTENNAGATEAREA 0.647700 ;
    ANTENNADIFFAREA 0.434700 ;
    PORT
      LAYER met2 ;
        RECT 152.810 572.410 153.090 572.690 ;
    END
  END s_axi_araddr_7
  PIN s_axi_araddr_8
    DIRECTION INPUT ;
    USE SIGNAL ;
    ANTENNAGATEAREA 0.647700 ;
    ANTENNADIFFAREA 0.434700 ;
    PORT
      LAYER met3 ;
        RECT 0.000 428.440 0.600 429.040 ;
    END
  END s_axi_araddr_8
  PIN s_axi_araddr_9
    DIRECTION INPUT ;
    USE SIGNAL ;
    ANTENNAGATEAREA 0.647700 ;
    ANTENNADIFFAREA 0.434700 ;
    PORT
      LAYER met2 ;
        RECT 99.450 572.410 99.730 572.690 ;
    END
  END s_axi_araddr_9
  PIN s_axi_arready
    DIRECTION OUTPUT ;
    USE SIGNAL ;
    ANTENNAGATEAREA 0.434700 ;
    ANTENNADIFFAREA 1.137600 ;
    PORT
      LAYER met2 ;
        RECT 169.370 572.410 169.650 572.690 ;
    END
  END s_axi_arready
  PIN s_axi_arvalid
    DIRECTION INPUT ;
    USE SIGNAL ;
    ANTENNAGATEAREA 0.647700 ;
    ANTENNADIFFAREA 0.434700 ;
    PORT
      LAYER met2 ;
        RECT 167.530 572.410 167.810 572.690 ;
    END
  END s_axi_arvalid
  PIN s_axi_awaddr_0
    DIRECTION INPUT ;
    USE SIGNAL ;
    ANTENNAGATEAREA 0.647700 ;
    ANTENNADIFFAREA 0.434700 ;
    PORT
      LAYER met2 ;
        RECT 222.730 572.410 223.010 572.690 ;
    END
  END s_axi_awaddr_0
  PIN s_axi_awaddr_1
    DIRECTION INPUT ;
    USE SIGNAL ;
    ANTENNAGATEAREA 0.647700 ;
    ANTENNADIFFAREA 0.434700 ;
    PORT
      LAYER met2 ;
        RECT 208.930 572.410 209.210 572.690 ;
    END
  END s_axi_awaddr_1
  PIN s_axi_awaddr_10
    DIRECTION INPUT ;
    USE SIGNAL ;
    ANTENNAGATEAREA 0.647700 ;
    ANTENNADIFFAREA 0.434700 ;
    PORT
      LAYER met2 ;
        RECT 221.810 572.410 222.090 572.690 ;
    END
  END s_axi_awaddr_10
  PIN s_axi_awaddr_11
    DIRECTION INPUT ;
    USE SIGNAL ;
    ANTENNAGATEAREA 0.647700 ;
    ANTENNADIFFAREA 0.434700 ;
    PORT
      LAYER met2 ;
        RECT 209.850 572.410 210.130 572.690 ;
    END
  END s_axi_awaddr_11
  PIN s_axi_awaddr_2
    DIRECTION INPUT ;
    USE SIGNAL ;
    ANTENNAGATEAREA 0.647700 ;
    ANTENNADIFFAREA 0.434700 ;
    PORT
      LAYER met2 ;
        RECT 273.330 572.410 273.610 572.690 ;
    END
  END s_axi_awaddr_2
  PIN s_axi_awaddr_3
    DIRECTION INPUT ;
    USE SIGNAL ;
    ANTENNAGATEAREA 0.647700 ;
    ANTENNADIFFAREA 0.434700 ;
    PORT
      LAYER met2 ;
        RECT 256.770 572.410 257.050 572.690 ;
    END
  END s_axi_awaddr_3
  PIN s_axi_awaddr_4
    DIRECTION INPUT ;
    USE SIGNAL ;
    ANTENNAGATEAREA 0.647700 ;
    ANTENNADIFFAREA 0.434700 ;
    PORT
      LAYER met2 ;
        RECT 272.410 572.410 272.690 572.690 ;
    END
  END s_axi_awaddr_4
  PIN s_axi_awaddr_5
    DIRECTION INPUT ;
    USE SIGNAL ;
    ANTENNAGATEAREA 0.647700 ;
    ANTENNADIFFAREA 0.434700 ;
    PORT
      LAYER met2 ;
        RECT 210.770 572.410 211.050 572.690 ;
    END
  END s_axi_awaddr_5
  PIN s_axi_awaddr_6
    DIRECTION INPUT ;
    USE SIGNAL ;
    ANTENNAGATEAREA 0.647700 ;
    ANTENNADIFFAREA 0.434700 ;
    PORT
      LAYER met2 ;
        RECT 223.650 572.410 223.930 572.690 ;
    END
  END s_axi_awaddr_6
  PIN s_axi_awaddr_7
    DIRECTION INPUT ;
    USE SIGNAL ;
    ANTENNAGATEAREA 0.647700 ;
    ANTENNADIFFAREA 0.434700 ;
    PORT
      LAYER met2 ;
        RECT 238.370 572.410 238.650 572.690 ;
    END
  END s_axi_awaddr_7
  PIN s_axi_awaddr_8
    DIRECTION INPUT ;
    USE SIGNAL ;
    ANTENNAGATEAREA 0.647700 ;
    ANTENNADIFFAREA 0.434700 ;
    PORT
      LAYER met2 ;
        RECT 270.570 572.410 270.850 572.690 ;
    END
  END s_axi_awaddr_8
  PIN s_axi_awaddr_9
    DIRECTION INPUT ;
    USE SIGNAL ;
    ANTENNAGATEAREA 0.647700 ;
    ANTENNADIFFAREA 0.434700 ;
    PORT
      LAYER met2 ;
        RECT 255.850 572.410 256.130 572.690 ;
    END
  END s_axi_awaddr_9
  PIN s_axi_awready
    DIRECTION OUTPUT ;
    USE SIGNAL ;
    PORT
      LAYER met2 ;
        RECT 1.930 0.000 2.210 0.280 ;
    END
  END s_axi_awready
  PIN s_axi_awvalid
    DIRECTION INPUT ;
    USE SIGNAL ;
    ANTENNAGATEAREA 0.647700 ;
    ANTENNADIFFAREA 0.434700 ;
    PORT
      LAYER met2 ;
        RECT 269.650 572.410 269.930 572.690 ;
    END
  END s_axi_awvalid
  PIN s_axi_bready
    DIRECTION INPUT ;
    USE SIGNAL ;
    ANTENNAGATEAREA 0.647700 ;
    ANTENNADIFFAREA 0.434700 ;
    PORT
      LAYER met2 ;
        RECT 288.050 572.410 288.330 572.690 ;
    END
  END s_axi_bready
  PIN s_axi_bresp_0
    DIRECTION OUTPUT ;
    USE SIGNAL ;
    ANTENNAGATEAREA 0.434700 ;
    ANTENNADIFFAREA 0.434700 ;
    PORT
      LAYER met3 ;
        RECT 0.000 439.320 0.600 439.920 ;
    END
  END s_axi_bresp_0
  PIN s_axi_bresp_1
    DIRECTION OUTPUT ;
    USE SIGNAL ;
    ANTENNAGATEAREA 0.434700 ;
    ANTENNADIFFAREA 0.775300 ;
    PORT
      LAYER met3 ;
        RECT 561.370 65.320 561.970 65.920 ;
    END
  END s_axi_bresp_1
  PIN s_axi_bvalid
    DIRECTION OUTPUT ;
    USE SIGNAL ;
    ANTENNAGATEAREA 0.434700 ;
    ANTENNADIFFAREA 1.137600 ;
    PORT
      LAYER met2 ;
        RECT 289.890 572.410 290.170 572.690 ;
    END
  END s_axi_bvalid
  PIN s_axi_rdata_0
    DIRECTION OUTPUT ;
    USE SIGNAL ;
    ANTENNAGATEAREA 0.434700 ;
    ANTENNADIFFAREA 1.137600 ;
    PORT
      LAYER met2 ;
        RECT 294.490 572.410 294.770 572.690 ;
    END
  END s_axi_rdata_0
  PIN s_axi_rdata_1
    DIRECTION OUTPUT ;
    USE SIGNAL ;
    ANTENNAGATEAREA 0.434700 ;
    ANTENNADIFFAREA 1.137600 ;
    PORT
      LAYER met2 ;
        RECT 315.650 572.410 315.930 572.690 ;
    END
  END s_axi_rdata_1
  PIN s_axi_rdata_10
    DIRECTION OUTPUT ;
    USE SIGNAL ;
    ANTENNAGATEAREA 0.434700 ;
    ANTENNADIFFAREA 1.137600 ;
    PORT
      LAYER met2 ;
        RECT 403.970 0.000 404.250 0.280 ;
    END
  END s_axi_rdata_10
  PIN s_axi_rdata_11
    DIRECTION OUTPUT ;
    USE SIGNAL ;
    ANTENNAGATEAREA 0.434700 ;
    ANTENNADIFFAREA 1.137600 ;
    PORT
      LAYER met2 ;
        RECT 265.050 0.000 265.330 0.280 ;
    END
  END s_axi_rdata_11
  PIN s_axi_rdata_12
    DIRECTION OUTPUT ;
    USE SIGNAL ;
    ANTENNAGATEAREA 0.434700 ;
    ANTENNADIFFAREA 1.137600 ;
    PORT
      LAYER met2 ;
        RECT 276.090 0.000 276.370 0.280 ;
    END
  END s_axi_rdata_12
  PIN s_axi_rdata_13
    DIRECTION OUTPUT ;
    USE SIGNAL ;
    ANTENNAGATEAREA 0.434700 ;
    ANTENNADIFFAREA 1.137600 ;
    PORT
      LAYER met3 ;
        RECT 561.370 315.560 561.970 316.160 ;
    END
  END s_axi_rdata_13
  PIN s_axi_rdata_14
    DIRECTION OUTPUT ;
    USE SIGNAL ;
    ANTENNAGATEAREA 0.434700 ;
    ANTENNADIFFAREA 1.137600 ;
    PORT
      LAYER met3 ;
        RECT 0.000 310.120 0.600 310.720 ;
    END
  END s_axi_rdata_14
  PIN s_axi_rdata_15
    DIRECTION OUTPUT ;
    USE SIGNAL ;
    ANTENNAGATEAREA 0.434700 ;
    ANTENNADIFFAREA 1.137600 ;
    PORT
      LAYER met3 ;
        RECT 0.000 273.400 0.600 274.000 ;
    END
  END s_axi_rdata_15
  PIN s_axi_rdata_16
    DIRECTION OUTPUT ;
    USE SIGNAL ;
    ANTENNAGATEAREA 0.434700 ;
    ANTENNADIFFAREA 1.137600 ;
    PORT
      LAYER met2 ;
        RECT 116.930 0.000 117.210 0.280 ;
    END
  END s_axi_rdata_16
  PIN s_axi_rdata_17
    DIRECTION OUTPUT ;
    USE SIGNAL ;
    ANTENNAGATEAREA 0.434700 ;
    ANTENNADIFFAREA 1.137600 ;
    PORT
      LAYER met2 ;
        RECT 104.050 0.000 104.330 0.280 ;
    END
  END s_axi_rdata_17
  PIN s_axi_rdata_18
    DIRECTION OUTPUT ;
    USE SIGNAL ;
    ANTENNAGATEAREA 0.434700 ;
    ANTENNADIFFAREA 1.137600 ;
    PORT
      LAYER met2 ;
        RECT 121.530 0.000 121.810 0.280 ;
    END
  END s_axi_rdata_18
  PIN s_axi_rdata_19
    DIRECTION OUTPUT ;
    USE SIGNAL ;
    ANTENNAGATEAREA 0.434700 ;
    ANTENNADIFFAREA 1.137600 ;
    PORT
      LAYER met2 ;
        RECT 169.370 0.000 169.650 0.280 ;
    END
  END s_axi_rdata_19
  PIN s_axi_rdata_2
    DIRECTION OUTPUT ;
    USE SIGNAL ;
    ANTENNAGATEAREA 0.434700 ;
    ANTENNADIFFAREA 1.137600 ;
    PORT
      LAYER met3 ;
        RECT 561.370 406.680 561.970 407.280 ;
    END
  END s_axi_rdata_2
  PIN s_axi_rdata_20
    DIRECTION OUTPUT ;
    USE SIGNAL ;
    ANTENNAGATEAREA 0.434700 ;
    ANTENNADIFFAREA 1.137600 ;
    PORT
      LAYER met3 ;
        RECT 0.000 144.200 0.600 144.800 ;
    END
  END s_axi_rdata_20
  PIN s_axi_rdata_21
    DIRECTION OUTPUT ;
    USE SIGNAL ;
    ANTENNAGATEAREA 0.434700 ;
    ANTENNADIFFAREA 1.137600 ;
    PORT
      LAYER met3 ;
        RECT 0.000 160.520 0.600 161.120 ;
    END
  END s_axi_rdata_21
  PIN s_axi_rdata_22
    DIRECTION OUTPUT ;
    USE SIGNAL ;
    ANTENNAGATEAREA 0.434700 ;
    ANTENNADIFFAREA 1.137600 ;
    PORT
      LAYER met3 ;
        RECT 0.000 191.800 0.600 192.400 ;
    END
  END s_axi_rdata_22
  PIN s_axi_rdata_23
    DIRECTION OUTPUT ;
    USE SIGNAL ;
    ANTENNAGATEAREA 0.434700 ;
    ANTENNADIFFAREA 1.137600 ;
    PORT
      LAYER met3 ;
        RECT 0.000 209.480 0.600 210.080 ;
    END
  END s_axi_rdata_23
  PIN s_axi_rdata_24
    DIRECTION OUTPUT ;
    USE SIGNAL ;
    ANTENNAGATEAREA 0.434700 ;
    ANTENNADIFFAREA 1.137600 ;
    PORT
      LAYER met3 ;
        RECT 0.000 276.120 0.600 276.720 ;
    END
  END s_axi_rdata_24
  PIN s_axi_rdata_25
    DIRECTION OUTPUT ;
    USE SIGNAL ;
    ANTENNAGATEAREA 0.434700 ;
    ANTENNADIFFAREA 1.137600 ;
    PORT
      LAYER met3 ;
        RECT 0.000 242.120 0.600 242.720 ;
    END
  END s_axi_rdata_25
  PIN s_axi_rdata_26
    DIRECTION OUTPUT ;
    USE SIGNAL ;
    ANTENNAGATEAREA 0.434700 ;
    ANTENNADIFFAREA 1.137600 ;
    PORT
      LAYER met3 ;
        RECT 0.000 292.440 0.600 293.040 ;
    END
  END s_axi_rdata_26
  PIN s_axi_rdata_27
    DIRECTION OUTPUT ;
    USE SIGNAL ;
    ANTENNAGATEAREA 0.434700 ;
    ANTENNADIFFAREA 1.137600 ;
    PORT
      LAYER met3 ;
        RECT 0.000 308.760 0.600 309.360 ;
    END
  END s_axi_rdata_27
  PIN s_axi_rdata_28
    DIRECTION OUTPUT ;
    USE SIGNAL ;
    ANTENNAGATEAREA 0.434700 ;
    ANTENNADIFFAREA 1.137600 ;
    PORT
      LAYER met3 ;
        RECT 0.000 342.760 0.600 343.360 ;
    END
  END s_axi_rdata_28
  PIN s_axi_rdata_29
    DIRECTION OUTPUT ;
    USE SIGNAL ;
    ANTENNAGATEAREA 0.434700 ;
    ANTENNADIFFAREA 1.137600 ;
    PORT
      LAYER met3 ;
        RECT 0.000 406.680 0.600 407.280 ;
    END
  END s_axi_rdata_29
  PIN s_axi_rdata_3
    DIRECTION OUTPUT ;
    USE SIGNAL ;
    ANTENNAGATEAREA 0.434700 ;
    ANTENNADIFFAREA 1.137600 ;
    PORT
      LAYER met2 ;
        RECT 333.130 572.410 333.410 572.690 ;
    END
  END s_axi_rdata_3
  PIN s_axi_rdata_30
    DIRECTION OUTPUT ;
    USE SIGNAL ;
    ANTENNAGATEAREA 0.434700 ;
    ANTENNADIFFAREA 1.137600 ;
    PORT
      LAYER met3 ;
        RECT 0.000 405.320 0.600 405.920 ;
    END
  END s_axi_rdata_30
  PIN s_axi_rdata_31
    DIRECTION OUTPUT ;
    USE SIGNAL ;
    ANTENNAGATEAREA 0.434700 ;
    ANTENNADIFFAREA 1.137600 ;
    PORT
      LAYER met3 ;
        RECT 0.000 416.200 0.600 416.800 ;
    END
  END s_axi_rdata_31
  PIN s_axi_rdata_4
    DIRECTION OUTPUT ;
    USE SIGNAL ;
    ANTENNAGATEAREA 0.434700 ;
    ANTENNADIFFAREA 1.137600 ;
    PORT
      LAYER met3 ;
        RECT 561.370 239.400 561.970 240.000 ;
    END
  END s_axi_rdata_4
  PIN s_axi_rdata_5
    DIRECTION OUTPUT ;
    USE SIGNAL ;
    ANTENNAGATEAREA 0.434700 ;
    ANTENNADIFFAREA 1.137600 ;
    PORT
      LAYER met3 ;
        RECT 561.370 167.320 561.970 167.920 ;
    END
  END s_axi_rdata_5
  PIN s_axi_rdata_6
    DIRECTION OUTPUT ;
    USE SIGNAL ;
    ANTENNAGATEAREA 0.434700 ;
    ANTENNADIFFAREA 1.137600 ;
    PORT
      LAYER met2 ;
        RECT 373.610 0.000 373.890 0.280 ;
    END
  END s_axi_rdata_6
  PIN s_axi_rdata_7
    DIRECTION OUTPUT ;
    USE SIGNAL ;
    ANTENNAGATEAREA 0.434700 ;
    ANTENNADIFFAREA 1.137600 ;
    PORT
      LAYER met2 ;
        RECT 391.090 0.000 391.370 0.280 ;
    END
  END s_axi_rdata_7
  PIN s_axi_rdata_8
    DIRECTION OUTPUT ;
    USE SIGNAL ;
    ANTENNAGATEAREA 0.434700 ;
    ANTENNADIFFAREA 1.137600 ;
    PORT
      LAYER met2 ;
        RECT 224.570 0.000 224.850 0.280 ;
    END
  END s_axi_rdata_8
  PIN s_axi_rdata_9
    DIRECTION OUTPUT ;
    USE SIGNAL ;
    ANTENNAGATEAREA 0.434700 ;
    ANTENNADIFFAREA 1.137600 ;
    PORT
      LAYER met2 ;
        RECT 286.210 0.000 286.490 0.280 ;
    END
  END s_axi_rdata_9
  PIN s_axi_rready
    DIRECTION INPUT ;
    USE SIGNAL ;
    ANTENNAGATEAREA 0.647700 ;
    ANTENNADIFFAREA 0.434700 ;
    PORT
      LAYER met3 ;
        RECT 0.000 450.200 0.600 450.800 ;
    END
  END s_axi_rready
  PIN s_axi_rresp_0
    DIRECTION OUTPUT ;
    USE SIGNAL ;
    ANTENNAGATEAREA 0.434700 ;
    ANTENNADIFFAREA 0.775300 ;
    PORT
      LAYER met3 ;
        RECT 561.370 87.080 561.970 87.680 ;
    END
  END s_axi_rresp_0
  PIN s_axi_rresp_1
    DIRECTION OUTPUT ;
    USE SIGNAL ;
    ANTENNAGATEAREA 0.434700 ;
    ANTENNADIFFAREA 0.775300 ;
    PORT
      LAYER met3 ;
        RECT 561.370 111.560 561.970 112.160 ;
    END
  END s_axi_rresp_1
  PIN s_axi_rvalid
    DIRECTION OUTPUT ;
    USE SIGNAL ;
    ANTENNAGATEAREA 0.434700 ;
    ANTENNADIFFAREA 1.137600 ;
    PORT
      LAYER met3 ;
        RECT 0.000 448.840 0.600 449.440 ;
    END
  END s_axi_rvalid
  PIN s_axi_wdata_0
    DIRECTION INPUT ;
    USE SIGNAL ;
    ANTENNAGATEAREA 0.647700 ;
    ANTENNADIFFAREA 0.434700 ;
    PORT
      LAYER met2 ;
        RECT 239.290 572.410 239.570 572.690 ;
    END
  END s_axi_wdata_0
  PIN s_axi_wdata_1
    DIRECTION INPUT ;
    USE SIGNAL ;
    ANTENNAGATEAREA 0.647700 ;
    ANTENNADIFFAREA 0.434700 ;
    PORT
      LAYER met2 ;
        RECT 254.930 572.410 255.210 572.690 ;
    END
  END s_axi_wdata_1
  PIN s_axi_wdata_10
    DIRECTION INPUT ;
    USE SIGNAL ;
    ANTENNAGATEAREA 0.647700 ;
    ANTENNADIFFAREA 0.434700 ;
    PORT
      LAYER met2 ;
        RECT 329.450 0.000 329.730 0.280 ;
    END
  END s_axi_wdata_10
  PIN s_axi_wdata_11
    DIRECTION INPUT ;
    USE SIGNAL ;
    ANTENNAGATEAREA 0.647700 ;
    ANTENNADIFFAREA 0.434700 ;
    PORT
      LAYER met2 ;
        RECT 210.770 0.000 211.050 0.280 ;
    END
  END s_axi_wdata_11
  PIN s_axi_wdata_12
    DIRECTION INPUT ;
    USE SIGNAL ;
    ANTENNAGATEAREA 0.647700 ;
    ANTENNADIFFAREA 0.434700 ;
    PORT
      LAYER met2 ;
        RECT 238.370 0.000 238.650 0.280 ;
    END
  END s_axi_wdata_12
  PIN s_axi_wdata_13
    DIRECTION INPUT ;
    USE SIGNAL ;
    ANTENNAGATEAREA 0.647700 ;
    ANTENNADIFFAREA 0.434700 ;
    PORT
      LAYER met3 ;
        RECT 561.370 287.000 561.970 287.600 ;
    END
  END s_axi_wdata_13
  PIN s_axi_wdata_14
    DIRECTION INPUT ;
    USE SIGNAL ;
    ANTENNAGATEAREA 0.647700 ;
    ANTENNADIFFAREA 0.434700 ;
    PORT
      LAYER met2 ;
        RECT 220.890 0.000 221.170 0.280 ;
    END
  END s_axi_wdata_14
  PIN s_axi_wdata_15
    DIRECTION INPUT ;
    USE SIGNAL ;
    ANTENNAGATEAREA 0.647700 ;
    ANTENNADIFFAREA 0.434700 ;
    PORT
      LAYER met3 ;
        RECT 0.000 240.760 0.600 241.360 ;
    END
  END s_axi_wdata_15
  PIN s_axi_wdata_16
    DIRECTION INPUT ;
    USE SIGNAL ;
    ANTENNAGATEAREA 0.647700 ;
    ANTENNADIFFAREA 0.434700 ;
    PORT
      LAYER met2 ;
        RECT 69.090 0.000 69.370 0.280 ;
    END
  END s_axi_wdata_16
  PIN s_axi_wdata_17
    DIRECTION INPUT ;
    USE SIGNAL ;
    ANTENNAGATEAREA 0.647700 ;
    ANTENNADIFFAREA 0.434700 ;
    PORT
      LAYER met2 ;
        RECT 63.570 0.000 63.850 0.280 ;
    END
  END s_axi_wdata_17
  PIN s_axi_wdata_18
    DIRECTION INPUT ;
    USE SIGNAL ;
    ANTENNAGATEAREA 0.647700 ;
    ANTENNADIFFAREA 0.434700 ;
    PORT
      LAYER met2 ;
        RECT 74.610 0.000 74.890 0.280 ;
    END
  END s_axi_wdata_18
  PIN s_axi_wdata_19
    DIRECTION INPUT ;
    USE SIGNAL ;
    ANTENNAGATEAREA 0.647700 ;
    ANTENNADIFFAREA 0.434700 ;
    PORT
      LAYER met2 ;
        RECT 205.250 0.000 205.530 0.280 ;
    END
  END s_axi_wdata_19
  PIN s_axi_wdata_2
    DIRECTION INPUT ;
    USE SIGNAL ;
    ANTENNAGATEAREA 0.647700 ;
    ANTENNADIFFAREA 0.434700 ;
    PORT
      LAYER met2 ;
        RECT 341.410 572.410 341.690 572.690 ;
    END
  END s_axi_wdata_2
  PIN s_axi_wdata_20
    DIRECTION INPUT ;
    USE SIGNAL ;
    ANTENNAGATEAREA 0.647700 ;
    ANTENNADIFFAREA 0.434700 ;
    PORT
      LAYER met3 ;
        RECT 0.000 138.760 0.600 139.360 ;
    END
  END s_axi_wdata_20
  PIN s_axi_wdata_21
    DIRECTION INPUT ;
    USE SIGNAL ;
    ANTENNAGATEAREA 0.647700 ;
    ANTENNADIFFAREA 0.434700 ;
    PORT
      LAYER met3 ;
        RECT 0.000 149.640 0.600 150.240 ;
    END
  END s_axi_wdata_21
  PIN s_axi_wdata_22
    DIRECTION INPUT ;
    USE SIGNAL ;
    ANTENNAGATEAREA 0.647700 ;
    ANTENNADIFFAREA 0.434700 ;
    PORT
      LAYER met3 ;
        RECT 0.000 180.920 0.600 181.520 ;
    END
  END s_axi_wdata_22
  PIN s_axi_wdata_23
    DIRECTION INPUT ;
    USE SIGNAL ;
    ANTENNAGATEAREA 0.647700 ;
    ANTENNADIFFAREA 0.434700 ;
    PORT
      LAYER met3 ;
        RECT 0.000 199.960 0.600 200.560 ;
    END
  END s_axi_wdata_23
  PIN s_axi_wdata_24
    DIRECTION INPUT ;
    USE SIGNAL ;
    ANTENNAGATEAREA 0.647700 ;
    ANTENNADIFFAREA 0.434700 ;
    PORT
      LAYER met3 ;
        RECT 0.000 278.840 0.600 279.440 ;
    END
  END s_axi_wdata_24
  PIN s_axi_wdata_25
    DIRECTION INPUT ;
    USE SIGNAL ;
    ANTENNAGATEAREA 0.647700 ;
    ANTENNADIFFAREA 0.434700 ;
    PORT
      LAYER met3 ;
        RECT 0.000 228.520 0.600 229.120 ;
    END
  END s_axi_wdata_25
  PIN s_axi_wdata_26
    DIRECTION INPUT ;
    USE SIGNAL ;
    ANTENNAGATEAREA 0.647700 ;
    ANTENNADIFFAREA 0.434700 ;
    PORT
      LAYER met3 ;
        RECT 0.000 304.680 0.600 305.280 ;
    END
  END s_axi_wdata_26
  PIN s_axi_wdata_27
    DIRECTION INPUT ;
    USE SIGNAL ;
    ANTENNAGATEAREA 0.647700 ;
    ANTENNADIFFAREA 0.434700 ;
    PORT
      LAYER met3 ;
        RECT 0.000 318.280 0.600 318.880 ;
    END
  END s_axi_wdata_27
  PIN s_axi_wdata_28
    DIRECTION INPUT ;
    USE SIGNAL ;
    ANTENNAGATEAREA 0.647700 ;
    ANTENNADIFFAREA 0.434700 ;
    PORT
      LAYER met3 ;
        RECT 0.000 421.640 0.600 422.240 ;
    END
  END s_axi_wdata_28
  PIN s_axi_wdata_29
    DIRECTION INPUT ;
    USE SIGNAL ;
    ANTENNAGATEAREA 0.647700 ;
    ANTENNADIFFAREA 0.434700 ;
    PORT
      LAYER met3 ;
        RECT 0.000 435.240 0.600 435.840 ;
    END
  END s_axi_wdata_29
  PIN s_axi_wdata_3
    DIRECTION INPUT ;
    USE SIGNAL ;
    ANTENNAGATEAREA 0.647700 ;
    ANTENNADIFFAREA 0.434700 ;
    PORT
      LAYER met2 ;
        RECT 343.250 572.410 343.530 572.690 ;
    END
  END s_axi_wdata_3
  PIN s_axi_wdata_30
    DIRECTION INPUT ;
    USE SIGNAL ;
    ANTENNAGATEAREA 0.647700 ;
    ANTENNADIFFAREA 0.434700 ;
    PORT
      LAYER met3 ;
        RECT 0.000 442.040 0.600 442.640 ;
    END
  END s_axi_wdata_30
  PIN s_axi_wdata_31
    DIRECTION INPUT ;
    USE SIGNAL ;
    ANTENNAGATEAREA 0.647700 ;
    ANTENNADIFFAREA 0.434700 ;
    PORT
      LAYER met3 ;
        RECT 0.000 425.720 0.600 426.320 ;
    END
  END s_axi_wdata_31
  PIN s_axi_wdata_4
    DIRECTION INPUT ;
    USE SIGNAL ;
    ANTENNAGATEAREA 0.647700 ;
    ANTENNADIFFAREA 0.434700 ;
    PORT
      LAYER met2 ;
        RECT 340.490 0.000 340.770 0.280 ;
    END
  END s_axi_wdata_4
  PIN s_axi_wdata_5
    DIRECTION INPUT ;
    USE SIGNAL ;
    ANTENNAGATEAREA 0.647700 ;
    ANTENNADIFFAREA 0.434700 ;
    PORT
      LAYER met2 ;
        RECT 318.410 0.000 318.690 0.280 ;
    END
  END s_axi_wdata_5
  PIN s_axi_wdata_6
    DIRECTION INPUT ;
    USE SIGNAL ;
    ANTENNAGATEAREA 0.647700 ;
    ANTENNADIFFAREA 0.434700 ;
    PORT
      LAYER met2 ;
        RECT 336.810 0.000 337.090 0.280 ;
    END
  END s_axi_wdata_6
  PIN s_axi_wdata_7
    DIRECTION INPUT ;
    USE SIGNAL ;
    ANTENNAGATEAREA 0.647700 ;
    ANTENNADIFFAREA 0.434700 ;
    PORT
      LAYER met2 ;
        RECT 347.850 0.000 348.130 0.280 ;
    END
  END s_axi_wdata_7
  PIN s_axi_wdata_8
    DIRECTION INPUT ;
    USE SIGNAL ;
    ANTENNAGATEAREA 0.647700 ;
    ANTENNADIFFAREA 0.434700 ;
    PORT
      LAYER met2 ;
        RECT 221.810 0.000 222.090 0.280 ;
    END
  END s_axi_wdata_8
  PIN s_axi_wdata_9
    DIRECTION INPUT ;
    USE SIGNAL ;
    ANTENNAGATEAREA 0.647700 ;
    ANTENNADIFFAREA 0.434700 ;
    PORT
      LAYER met2 ;
        RECT 271.490 0.000 271.770 0.280 ;
    END
  END s_axi_wdata_9
  PIN s_axi_wready
    DIRECTION OUTPUT ;
    USE SIGNAL ;
    PORT
      LAYER met2 ;
        RECT 2.850 0.000 3.130 0.280 ;
    END
  END s_axi_wready
  PIN s_axi_wstrb_0
    DIRECTION INPUT ;
    USE SIGNAL ;
    PORT
      LAYER met2 ;
        RECT 3.770 0.000 4.050 0.280 ;
    END
  END s_axi_wstrb_0
  PIN s_axi_wstrb_1
    DIRECTION INPUT ;
    USE SIGNAL ;
    PORT
      LAYER met2 ;
        RECT 4.690 0.000 4.970 0.280 ;
    END
  END s_axi_wstrb_1
  PIN s_axi_wstrb_2
    DIRECTION INPUT ;
    USE SIGNAL ;
    PORT
      LAYER met2 ;
        RECT 5.610 0.000 5.890 0.280 ;
    END
  END s_axi_wstrb_2
  PIN s_axi_wstrb_3
    DIRECTION INPUT ;
    USE SIGNAL ;
    PORT
      LAYER met2 ;
        RECT 6.530 0.000 6.810 0.280 ;
    END
  END s_axi_wstrb_3
  PIN s_axi_wvalid
    DIRECTION INPUT ;
    USE SIGNAL ;
    ANTENNAGATEAREA 0.647700 ;
    ANTENNADIFFAREA 0.434700 ;
    PORT
      LAYER met2 ;
        RECT 287.130 572.410 287.410 572.690 ;
    END
  END s_axi_wvalid
  OBS
      LAYER nwell ;
        RECT 5.330 10.795 556.330 560.405 ;
      LAYER li1 ;
        RECT 5.520 10.795 556.140 560.405 ;
      LAYER met1 ;
        RECT 2.370 10.640 556.140 560.560 ;
      LAYER met2 ;
        RECT 2.390 572.130 99.170 572.410 ;
        RECT 100.010 572.130 113.890 572.410 ;
        RECT 114.730 572.130 135.970 572.410 ;
        RECT 136.810 572.130 152.530 572.410 ;
        RECT 153.370 572.130 167.250 572.410 ;
        RECT 168.090 572.130 169.090 572.410 ;
        RECT 169.930 572.130 208.650 572.410 ;
        RECT 209.490 572.130 209.570 572.410 ;
        RECT 210.410 572.130 210.490 572.410 ;
        RECT 211.330 572.130 221.530 572.410 ;
        RECT 222.370 572.130 222.450 572.410 ;
        RECT 223.290 572.130 223.370 572.410 ;
        RECT 224.210 572.130 238.090 572.410 ;
        RECT 238.930 572.130 239.010 572.410 ;
        RECT 239.850 572.130 251.890 572.410 ;
        RECT 252.730 572.130 254.650 572.410 ;
        RECT 255.490 572.130 255.570 572.410 ;
        RECT 256.410 572.130 256.490 572.410 ;
        RECT 257.330 572.130 259.250 572.410 ;
        RECT 260.090 572.130 266.610 572.410 ;
        RECT 267.450 572.130 269.370 572.410 ;
        RECT 270.210 572.130 270.290 572.410 ;
        RECT 271.130 572.130 271.210 572.410 ;
        RECT 272.050 572.130 272.130 572.410 ;
        RECT 272.970 572.130 273.050 572.410 ;
        RECT 273.890 572.130 273.970 572.410 ;
        RECT 274.810 572.130 275.810 572.410 ;
        RECT 276.650 572.130 286.850 572.410 ;
        RECT 287.690 572.130 287.770 572.410 ;
        RECT 288.610 572.130 288.690 572.410 ;
        RECT 289.530 572.130 289.610 572.410 ;
        RECT 290.450 572.130 294.210 572.410 ;
        RECT 295.050 572.130 295.130 572.410 ;
        RECT 295.970 572.130 303.410 572.410 ;
        RECT 304.250 572.130 307.090 572.410 ;
        RECT 307.930 572.130 309.850 572.410 ;
        RECT 310.690 572.130 315.370 572.410 ;
        RECT 316.210 572.130 322.730 572.410 ;
        RECT 323.570 572.130 324.570 572.410 ;
        RECT 325.410 572.130 325.490 572.410 ;
        RECT 326.330 572.130 331.010 572.410 ;
        RECT 331.850 572.130 332.850 572.410 ;
        RECT 333.690 572.130 341.130 572.410 ;
        RECT 341.970 572.130 342.050 572.410 ;
        RECT 342.890 572.130 342.970 572.410 ;
        RECT 343.810 572.130 343.890 572.410 ;
        RECT 344.730 572.130 350.330 572.410 ;
        RECT 351.170 572.130 355.850 572.410 ;
        RECT 356.690 572.130 358.610 572.410 ;
        RECT 359.450 572.130 364.130 572.410 ;
        RECT 364.970 572.130 372.410 572.410 ;
        RECT 373.250 572.130 373.330 572.410 ;
        RECT 374.170 572.130 374.250 572.410 ;
        RECT 375.090 572.130 375.170 572.410 ;
        RECT 376.010 572.130 389.890 572.410 ;
        RECT 390.730 572.130 390.810 572.410 ;
        RECT 391.650 572.130 391.730 572.410 ;
        RECT 392.570 572.130 408.290 572.410 ;
        RECT 409.130 572.130 409.210 572.410 ;
        RECT 410.050 572.130 411.050 572.410 ;
        RECT 411.890 572.130 411.970 572.410 ;
        RECT 412.810 572.130 414.730 572.410 ;
        RECT 415.570 572.130 554.670 572.410 ;
        RECT 2.390 0.560 554.670 572.130 ;
        RECT 2.490 0.280 2.570 0.560 ;
        RECT 3.410 0.280 3.490 0.560 ;
        RECT 4.330 0.280 4.410 0.560 ;
        RECT 5.250 0.280 5.330 0.560 ;
        RECT 6.170 0.280 6.250 0.560 ;
        RECT 7.090 0.280 63.290 0.560 ;
        RECT 64.130 0.280 68.810 0.560 ;
        RECT 69.650 0.280 74.330 0.560 ;
        RECT 75.170 0.280 103.770 0.560 ;
        RECT 104.610 0.280 116.650 0.560 ;
        RECT 117.490 0.280 121.250 0.560 ;
        RECT 122.090 0.280 169.090 0.560 ;
        RECT 169.930 0.280 204.970 0.560 ;
        RECT 205.810 0.280 210.490 0.560 ;
        RECT 211.330 0.280 220.610 0.560 ;
        RECT 221.450 0.280 221.530 0.560 ;
        RECT 222.370 0.280 224.290 0.560 ;
        RECT 225.130 0.280 238.090 0.560 ;
        RECT 238.930 0.280 264.770 0.560 ;
        RECT 265.610 0.280 271.210 0.560 ;
        RECT 272.050 0.280 275.810 0.560 ;
        RECT 276.650 0.280 285.930 0.560 ;
        RECT 286.770 0.280 318.130 0.560 ;
        RECT 318.970 0.280 329.170 0.560 ;
        RECT 330.010 0.280 336.530 0.560 ;
        RECT 337.370 0.280 340.210 0.560 ;
        RECT 341.050 0.280 347.570 0.560 ;
        RECT 348.410 0.280 373.330 0.560 ;
        RECT 374.170 0.280 390.810 0.560 ;
        RECT 391.650 0.280 403.690 0.560 ;
        RECT 404.530 0.280 554.670 0.560 ;
      LAYER met3 ;
        RECT 0.600 554.560 561.370 560.485 ;
        RECT 1.000 553.160 561.370 554.560 ;
        RECT 0.600 453.920 561.370 553.160 ;
        RECT 1.000 447.080 561.370 453.920 ;
        RECT 0.600 443.040 561.370 447.080 ;
        RECT 1.000 421.240 561.370 443.040 ;
        RECT 0.600 417.200 561.370 421.240 ;
        RECT 1.000 415.800 561.370 417.200 ;
        RECT 0.600 407.680 561.370 415.800 ;
        RECT 1.000 406.280 560.970 407.680 ;
        RECT 1.000 404.920 561.370 406.280 ;
        RECT 0.600 343.760 561.370 404.920 ;
        RECT 1.000 342.360 561.370 343.760 ;
        RECT 0.600 319.280 561.370 342.360 ;
        RECT 1.000 317.880 561.370 319.280 ;
        RECT 0.600 316.560 561.370 317.880 ;
        RECT 0.600 315.160 560.970 316.560 ;
        RECT 0.600 311.120 561.370 315.160 ;
        RECT 1.000 308.360 561.370 311.120 ;
        RECT 0.600 305.680 561.370 308.360 ;
        RECT 1.000 304.280 561.370 305.680 ;
        RECT 0.600 293.440 561.370 304.280 ;
        RECT 1.000 292.040 561.370 293.440 ;
        RECT 0.600 288.000 561.370 292.040 ;
        RECT 0.600 286.600 560.970 288.000 ;
        RECT 0.600 279.840 561.370 286.600 ;
        RECT 1.000 278.440 561.370 279.840 ;
        RECT 0.600 277.120 561.370 278.440 ;
        RECT 1.000 275.720 561.370 277.120 ;
        RECT 0.600 274.400 561.370 275.720 ;
        RECT 1.000 273.000 561.370 274.400 ;
        RECT 0.600 243.120 561.370 273.000 ;
        RECT 1.000 240.400 561.370 243.120 ;
        RECT 1.000 240.360 560.970 240.400 ;
        RECT 0.600 239.000 560.970 240.360 ;
        RECT 0.600 229.520 561.370 239.000 ;
        RECT 1.000 228.120 561.370 229.520 ;
        RECT 0.600 210.480 561.370 228.120 ;
        RECT 1.000 209.080 561.370 210.480 ;
        RECT 0.600 200.960 561.370 209.080 ;
        RECT 1.000 199.560 561.370 200.960 ;
        RECT 0.600 192.800 561.370 199.560 ;
        RECT 1.000 191.400 561.370 192.800 ;
        RECT 0.600 181.920 561.370 191.400 ;
        RECT 1.000 180.520 561.370 181.920 ;
        RECT 0.600 168.320 561.370 180.520 ;
        RECT 0.600 166.920 560.970 168.320 ;
        RECT 0.600 161.520 561.370 166.920 ;
        RECT 1.000 160.120 561.370 161.520 ;
        RECT 0.600 150.640 561.370 160.120 ;
        RECT 1.000 149.240 561.370 150.640 ;
        RECT 0.600 145.200 561.370 149.240 ;
        RECT 1.000 143.800 561.370 145.200 ;
        RECT 0.600 139.760 561.370 143.800 ;
        RECT 1.000 138.360 561.370 139.760 ;
        RECT 0.600 134.320 561.370 138.360 ;
        RECT 0.600 47.240 560.970 134.320 ;
        RECT 0.600 29.600 561.370 47.240 ;
        RECT 0.600 28.200 560.970 29.600 ;
        RECT 0.600 10.715 561.370 28.200 ;
      LAYER met4 ;
        RECT 180.615 213.695 327.840 559.465 ;
        RECT 330.240 213.695 331.140 559.465 ;
        RECT 333.540 213.695 336.425 559.465 ;
  END
END dma_ctrl
END LIBRARY

